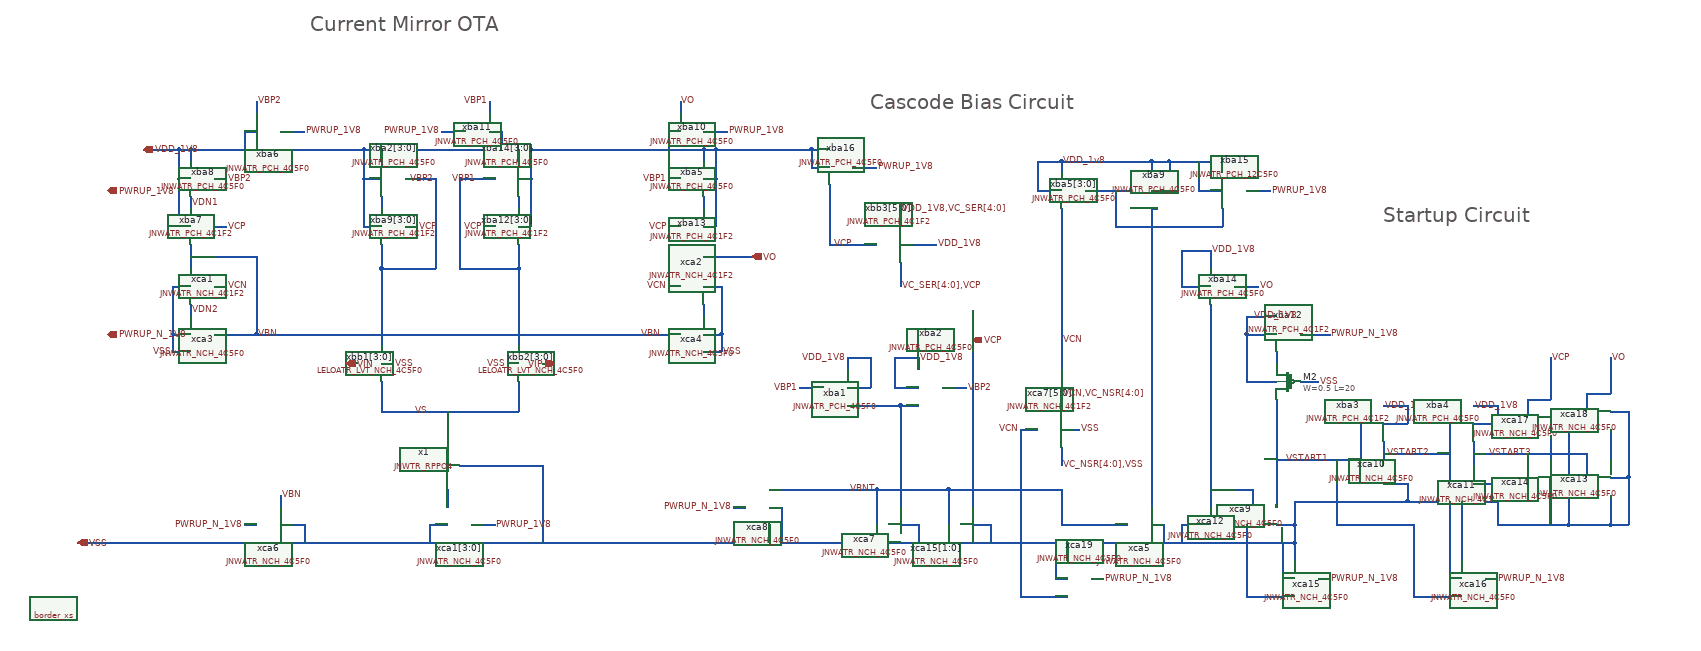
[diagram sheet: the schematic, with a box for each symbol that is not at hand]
v {xschem version=3.4.7 file_version=1.2}
G {}
K {}
V {}
S {}
E {}
T {Cascode Bias Circuit} 1430 -850 0 0 1 1 {}
T {Current Mirror OTA} 490 -980 0 0 1 1 {}
T {Startup Circuit} 2290 -660 0 0 1 1 {}
N 100 -100 210 -100 {lab=VSS}
N 210 -760 270 -760 {lab=VDD_1V8}
N 610 -370 610 -320 {lab=VS}
N 610 -320 840 -320 {lab=VS}
N 840 -370 840 -320 {lab=VS}
N 720 -320 720 -280 {lab=VS}
N 210 -100 720 -100 {lab=VSS}
N 610 -400 630 -400 {lab=VSS}
N 820 -400 840 -400 {lab=VSS}
N 580 -710 610 -710 {lab=VDD_1V8}
N 580 -760 580 -710 {lab=VDD_1V8}
N 580 -760 860 -760 {lab=VDD_1V8}
N 860 -760 860 -710 {lab=VDD_1V8}
N 840 -710 860 -710 {lab=VDD_1V8}
N 840 -760 840 -740 {lab=VDD_1V8}
N 610 -760 610 -740 {lab=VDD_1V8}
N 860 -710 860 -630 {lab=VDD_1V8}
N 840 -680 840 -660 {lab=#net1}
N 650 -710 700 -710 {lab=VBP2}
N 700 -710 700 -560 {lab=VBP2}
N 610 -560 700 -560 {lab=VBP2}
N 610 -590 610 -560 {lab=VBP2}
N 610 -560 610 -430 {lab=VBP2}
N 740 -710 800 -710 {lab=VBP1}
N 740 -710 740 -560 {lab=VBP1}
N 740 -560 840 -560 {lab=VBP1}
N 840 -600 840 -560 {lab=VBP1}
N 610 -600 610 -590 {lab=VBP2}
N 580 -710 580 -630 {lab=VDD_1V8}
N 840 -560 840 -430 {lab=VBP1}
N 1170 -760 1170 -710 {lab=VDD_1V8}
N 1150 -710 1170 -710 {lab=VDD_1V8}
N 1150 -760 1150 -740 {lab=VDD_1V8}
N 1170 -710 1170 -630 {lab=VDD_1V8}
N 1150 -680 1150 -660 {lab=#net2}
N 1150 -600 1150 -560 {lab=VO}
N 650 -630 670 -630 {lab=VCP}
N 780 -630 800 -630 {lab=VCP}
N 610 -680 610 -660 {lab=#net3}
N 1090 -710 1110 -710 {lab=VBP1}
N 1090 -630 1110 -630 {lab=VCP}
N 860 -760 1150 -760 {lab=VDD_1V8}
N 1150 -760 1170 -760 {lab=VDD_1V8}
N 270 -760 270 -710 {lab=VDD_1V8}
N 270 -710 290 -710 {lab=VDD_1V8}
N 290 -760 290 -740 {lab=VDD_1V8}
N 270 -710 270 -630 {lab=VDD_1V8}
N 290 -680 290 -660 {lab=VDN1}
N 290 -600 290 -560 {lab=VBN}
N 330 -710 350 -710 {lab=VBP2}
N 330 -630 350 -630 {lab=VCP}
N 290 -760 580 -760 {lab=VDD_1V8}
N 270 -760 290 -760 {lab=VDD_1V8}
N 290 -500 290 -480 {lab=VDN2}
N 260 -530 260 -450 {lab=VSS}
N 260 -450 290 -450 {lab=VSS}
N 260 -450 260 -420 {lab=VSS}
N 260 -420 290 -420 {lab=VSS}
N 330 -530 350 -530 {lab=VCN}
N 330 -450 400 -450 {lab=VBN}
N 400 -580 400 -450 {lab=VBN}
N 290 -580 400 -580 {lab=VBN}
N 1150 -600 1150 -560 {lab=VO}
N 1150 -500 1150 -480 {lab=#net4}
N 1180 -530 1180 -450 {lab=VSS}
N 1150 -450 1180 -450 {lab=VSS}
N 1180 -450 1180 -420 {lab=VSS}
N 1150 -420 1180 -420 {lab=VSS}
N 1090 -530 1110 -530 {lab=VCN}
N 1080 -450 1110 -450 {lab=VBN}
N 400 -450 1080 -450 {lab=VBN}
N 1150 -580 1230 -580 {lab=VO}
N 380 -790 400 -790 {lab=VDD_1V8}
N 380 -790 380 -760 {lab=VDD_1V8}
N 400 -840 400 -820 {lab=VBP2}
N 440 -790 480 -790 {lab=PWRUP_1V8}
N 790 -790 810 -790 {lab=VDD_1V8}
N 810 -790 810 -760 {lab=VDD_1V8}
N 790 -840 790 -820 {lab=VBP1}
N 710 -790 750 -790 {lab=PWRUP_1V8}
N 440 -130 480 -130 {lab=VSS}
N 480 -130 480 -100 {lab=VSS}
N 440 -180 440 -160 {lab=VBN}
N 380 -130 400 -130 {lab=PWRUP_N_1V8}
N 880 -400 900 -400 {lab=VIP}
N 550 -400 570 -400 {lab=VIN}
N 1480 -600 1510 -600 {lab=VDD_1V8}
N 1510 -600 1540 -600 {lab=VDD_1V8}
N 1400 -600 1440 -600 {lab=VCP}
N 1480 -670 1480 -630 {lab=VDD_1V8,VC_SER[4:0]}
N 1480 -570 1480 -530 {lab=VC_SER[4:0],VCP}
N 760 -100 1540 -100 {lab=VSS}
N 1280 -160 1280 -100 {lab=VSS}
N 1260 -160 1280 -160 {lab=VSS}
N 1260 -130 1260 -100 {lab=VSS}
N 1200 -160 1220 -160 {lab=PWRUP_N_1V8}
N 1750 -360 1750 -320 {lab=VCN,VC_NSR[4:0]}
N 1680 -290 1710 -290 {lab=VCN}
N 1750 -290 1780 -290 {lab=VSS}
N 1750 -260 1750 -230 {lab=VC_NSR[4:0],VSS}
N 1090 -790 1110 -790 {lab=VDD_1V8}
N 1090 -790 1090 -760 {lab=VDD_1V8}
N 1110 -840 1110 -820 {lab=VO}
N 1150 -790 1190 -790 {lab=PWRUP_1V8}
N 1540 -100 2140 -100 {lab=VSS}
N 1310 -360 1350 -360 {lab=VBP1}
N 1390 -360 1430 -360 {lab=VDD_1V8}
N 1430 -410 1430 -360 {lab=VDD_1V8}
N 1390 -410 1430 -410 {lab=VDD_1V8}
N 1390 -410 1390 -390 {lab=VDD_1V8}
N 1480 -130 1510 -130 {lab=VSS}
N 1510 -130 1510 -100 {lab=VSS}
N 1480 -100 1510 -100 {lab=VSS}
N 1480 -330 1480 -160 {lab=VBNT}
N 1440 -190 1440 -130 {lab=VBNT}
N 1440 -190 1480 -190 {lab=VBNT}
N 1710 -690 1750 -690 {lab=VDD_1v8}
N 1710 -740 1710 -690 {lab=VDD_1v8}
N 1710 -740 1750 -740 {lab=VDD_1v8}
N 1750 -740 1750 -720 {lab=VDD_1v8}
N 1750 -660 1750 -490 {lab=VCN}
N 1750 -490 1750 -390 {lab=VCN}
N 1260 -190 1440 -190 {lab=VBNT}
N 720 -100 760 -100 {lab=VSS}
N 690 -130 720 -130 {lab=VSS}
N 690 -130 690 -100 {lab=VSS}
N 760 -130 800 -130 {lab=PWRUP_1V8}
N 1600 -130 1630 -130 {lab=VSS}
N 1630 -130 1630 -100 {lab=VSS}
N 1560 -190 1560 -130 {lab=VBNT}
N 1480 -190 1560 -190 {lab=VBNT}
N 1600 -490 1600 -160 {lab=VCP}
N 2110 -130 2140 -130 {lab=VSS}
N 2140 -130 2140 -100 {lab=VSS}
N 2070 -190 2070 -130 {lab=#net5}
N 2110 -270 2110 -230 {lab=VSTART1}
N 2110 -230 2110 -160 {lab=VSTART1}
N 2290 -270 2290 -230 {lab=VSTART2}
N 2290 -200 2330 -200 {lab=VSS}
N 2330 -200 2330 -170 {lab=VSS}
N 2290 -170 2330 -170 {lab=VSS}
N 2140 -170 2290 -170 {lab=VSS}
N 2140 -170 2140 -130 {lab=VSS}
N 2250 -300 2250 -200 {lab=VSTART1}
N 2110 -240 2250 -240 {lab=VSTART1}
N 2290 -300 2330 -300 {lab=VDD_1V8}
N 2330 -330 2330 -300 {lab=VDD_1V8}
N 2290 -330 2330 -330 {lab=VDD_1V8}
N 2440 -270 2440 -230 {lab=VSTART3}
N 2440 -200 2480 -200 {lab=VSS}
N 2480 -200 2480 -170 {lab=VSS}
N 2440 -170 2480 -170 {lab=VSS}
N 2400 -300 2400 -200 {lab=VSTART2}
N 2440 -300 2480 -300 {lab=VDD_1V8}
N 2480 -330 2480 -300 {lab=VDD_1V8}
N 2440 -330 2480 -330 {lab=VDD_1V8}
N 2290 -250 2400 -250 {lab=VSTART2}
N 2480 -130 2550 -130 {lab=VSS}
N 2550 -130 2580 -130 {lab=VSS}
N 2670 -180 2670 -130 {lab=VSS}
N 2600 -130 2670 -130 {lab=VSS}
N 2670 -210 2700 -210 {lab=VSS}
N 2700 -210 2700 -130 {lab=VSS}
N 2670 -130 2700 -130 {lab=VSS}
N 2580 -130 2600 -130 {lab=VSS}
N 2510 -250 2630 -250 {lab=VSTART3}
N 2630 -250 2630 -210 {lab=VSTART3}
N 2480 -170 2480 -130 {lab=VSS}
N 2330 -170 2440 -170 {lab=VSS}
N 2110 -340 2110 -270 {lab=VSTART1}
N 2060 -370 2110 -370 {lab=VDD_1V8}
N 2060 -420 2060 -370 {lab=VDD_1V8}
N 2110 -420 2110 -400 {lab=#net6}
N 2150 -370 2180 -370 {lab=VSS}
N 2440 -250 2510 -250 {lab=VSTART3}
N 1550 -360 1590 -360 {lab=VBP2}
N 1470 -360 1510 -360 {lab=VDD_1V8}
N 1470 -410 1470 -360 {lab=VDD_1V8}
N 1470 -410 1510 -410 {lab=VDD_1V8}
N 1510 -410 1510 -390 {lab=VDD_1V8}
N 1390 -330 1480 -330 {lab=VBNT}
N 270 -630 290 -630 {lab=VDD_1V8}
N 260 -530 290 -530 {lab=VSS}
N 580 -630 610 -630 {lab=VDD_1V8}
N 840 -630 860 -630 {lab=VDD_1V8}
N 1150 -630 1170 -630 {lab=VDD_1V8}
N 1790 -690 1860 -690 {lab=#net7}
N 1750 -740 1900 -740 {lab=VDD_1v8}
N 1900 -740 1900 -720 {lab=VDD_1v8}
N 1900 -690 1930 -690 {lab=VDD_1v8}
N 1930 -740 1930 -690 {lab=VDD_1v8}
N 1900 -740 1930 -740 {lab=VDD_1v8}
N 1900 -660 1900 -160 {lab=#net7}
N 1900 -660 1910 -660 {lab=#net7}
N 1900 -130 1920 -130 {lab=VSS}
N 1920 -130 1920 -100 {lab=VSS}
N 1750 -190 1750 -130 {lab=VBNT}
N 1840 -690 1840 -630 {lab=#net7}
N 1840 -630 1900 -630 {lab=#net7}
N 1360 -600 1400 -600 {lab=VCP}
N 720 -280 720 -270 {lab=VS}
N 720 -190 720 -160 {lab=#net8}
N 740 -230 880 -230 {lab=VSS}
N 880 -230 880 -100 {lab=VSS}
N 1480 -330 1510 -330 {lab=VBNT}
N 2040 -130 2070 -130 {lab=#net5}
N 2000 -500 2000 -160 {lab=#net5}
N 1950 -590 1950 -530 {lab=VDD_1V8}
N 2000 -590 2000 -560 {lab=VDD_1V8}
N 2040 -530 2080 -530 {lab=VO}
N 2000 -190 2070 -190 {lab=#net5}
N 2570 -210 2600 -210 {lab=VSS}
N 2600 -210 2600 -130 {lab=VSS}
N 2570 -180 2570 -130 {lab=VSS}
N 2530 -250 2530 -210 {lab=VSTART3}
N 2570 -410 2570 -400 {lab=VCP}
N 1150 -530 1180 -530 {lab=VSS}
N 1950 -530 2000 -530 {lab=VDD_1V8}
N 1950 -590 2000 -590 {lab=VDD_1V8}
N 1750 -130 1860 -130 {lab=VBNT}
N 1560 -190 1750 -190 {lab=VBNT}
N 1970 -130 2000 -130 {lab=VSS}
N 1950 -130 1970 -130 {lab=VSS}
N 1950 -130 1950 -100 {lab=VSS}
N 2120 -100 2120 -40 {lab=VSS}
N 2120 -40 2140 -40 {lab=VSS}
N 2140 -100 2140 -70 {lab=VSS}
N 2180 -40 2200 -40 {lab=PWRUP_N_1V8}
N 2060 -10 2140 -10 {lab=#net5}
N 2060 -130 2060 -10 {lab=#net5}
N 2060 -450 2110 -450 {lab=VDD_1V8}
N 2060 -450 2060 -420 {lab=VDD_1V8}
N 2060 -480 2060 -450 {lab=VDD_1V8}
N 2060 -480 2110 -480 {lab=VDD_1V8}
N 2150 -450 2200 -450 {lab=PWRUP_N_1V8}
N 2400 -100 2400 -40 {lab=VSS}
N 2400 -40 2420 -40 {lab=VSS}
N 2420 -100 2420 -70 {lab=VSS}
N 2460 -40 2480 -40 {lab=PWRUP_N_1V8}
N 2340 -10 2420 -10 {lab=VSTART1}
N 2340 -130 2340 -10 {lab=VSTART1}
N 2420 -170 2420 -100 {lab=VSS}
N 2400 -170 2400 -100 {lab=VSS}
N 2210 -130 2340 -130 {lab=VSTART1}
N 2210 -240 2210 -130 {lab=VSTART1}
N 2570 -280 2570 -240 {lab=#net9}
N 2570 -310 2600 -310 {lab=VSS}
N 2600 -310 2600 -210 {lab=VSS}
N 2530 -340 2530 -310 {lab=VCP}
N 2530 -340 2570 -340 {lab=VCP}
N 2570 -400 2570 -340 {lab=VCP}
N 2670 -320 2700 -320 {lab=VSS}
N 2630 -350 2630 -320 {lab=VO}
N 2630 -350 2670 -350 {lab=VO}
N 2670 -290 2670 -240 {lab=#net10}
N 2700 -320 2700 -210 {lab=VSS}
N 2670 -410 2670 -350 {lab=VO}
N 2020 -660 2020 -630 {lab=#net7}
N 1900 -630 2020 -630 {lab=#net7}
N 2020 -740 2020 -720 {lab=VDD_1v8}
N 1930 -740 2020 -740 {lab=VDD_1v8}
N 1980 -690 2020 -690 {lab=VDD_1v8}
N 1980 -740 1980 -690 {lab=VDD_1v8}
N 2060 -690 2100 -690 {lab=PWRUP_1V8}
N 1330 -730 1360 -730 {lab=VDD_1V8}
N 1330 -760 1330 -730 {lab=VDD_1V8}
N 1330 -760 1360 -760 {lab=VDD_1V8}
N 1170 -760 1330 -760 {lab=VDD_1V8}
N 1360 -700 1360 -600 {lab=VCP}
N 1400 -730 1440 -730 {lab=PWRUP_1V8}
N 1740 -100 1740 -40 {lab=VSS}
N 1740 -40 1760 -40 {lab=VSS}
N 1760 -100 1760 -70 {lab=VSS}
N 1800 -40 1820 -40 {lab=PWRUP_N_1V8}
N 1680 -10 1760 -10 {lab=VCN}
N 1680 -290 1680 -10 {lab=VCN}
C {devices/ipin.sym} 210 -760 2 1 {name=p4 lab=VDD_1V8}
C {devices/ipin.sym} 100 -100 2 1 {name=p5 lab=VSS}
C {JNW_ATR_SKY130A/JNWATR_NCH_4C5F0.sym} 330 -450 0 1 {name=xca3}
C {devices/ipin.sym} 150 -450 2 1 {name=p9 lab=PWRUP_N_1V8}
C {devices/ipin.sym} 150 -690 2 1 {name=p10 lab=PWRUP_1V8}
C {cborder/border_xs.sym} 60 10 0 0 {user="Carsten Wulff" company="Carsten Wulff Software"}
C {LELO_ATR_SKY130A/LELOATR_LVT_NCH_4C5F0.sym} 570 -400 0 0 {name=xbb1[3:0]}
C {LELO_ATR_SKY130A/LELOATR_LVT_NCH_4C5F0.sym} 880 -400 0 1 {name=xbb2[3:0]}
C {devices/lab_wire.sym} 630 -400 0 1 {name=p1 sig_type=std_logic lab=VSS}
C {devices/lab_wire.sym} 820 -400 0 0 {name=p2 sig_type=std_logic lab=VSS}
C {devices/lab_wire.sym} 690 -320 0 0 {name=p7 sig_type=std_logic lab=VS}
C {JNW_ATR_SKY130A/JNWATR_PCH_4C5F0.sym} 650 -710 0 1 {name=xba2[3:0]}
C {JNW_ATR_SKY130A/JNWATR_PCH_4C5F0.sym} 800 -710 0 0 {name=xba14[3:0]}
C {JNW_ATR_SKY130A/JNWATR_PCH_4C5F0.sym} 1110 -710 0 0 {name=xba5}
C {devices/lab_wire.sym} 670 -630 0 1 {name=p8 sig_type=std_logic lab=VCP}
C {devices/lab_wire.sym} 780 -630 0 0 {name=p11 sig_type=std_logic lab=VCP}
C {devices/lab_wire.sym} 770 -710 0 0 {name=p12 sig_type=std_logic lab=VBP1}
C {devices/lab_wire.sym} 700 -710 0 0 {name=p14 sig_type=std_logic lab=VBP2}
C {devices/lab_wire.sym} 1090 -710 0 0 {name=p16 sig_type=std_logic lab=VBP1}
C {devices/lab_wire.sym} 1090 -630 0 0 {name=p17 sig_type=std_logic lab=VCP}
C {JNW_ATR_SKY130A/JNWATR_PCH_4C5F0.sym} 330 -710 0 1 {name=xba8}
C {devices/lab_wire.sym} 350 -710 0 1 {name=p18 sig_type=std_logic lab=VBP2
}
C {devices/lab_wire.sym} 350 -630 0 1 {name=p19 sig_type=std_logic lab=VCP}
C {devices/lab_wire.sym} 350 -530 0 1 {name=p13 sig_type=std_logic lab=VCN}
C {devices/lab_wire.sym} 400 -450 0 1 {name=p20 sig_type=std_logic lab=VBN}
C {devices/lab_wire.sym} 260 -420 0 0 {name=p21 sig_type=std_logic lab=VSS}
C {JNW_ATR_SKY130A/JNWATR_NCH_4C5F0.sym} 1110 -450 0 0 {name=xca4}
C {devices/lab_wire.sym} 1090 -530 0 0 {name=p22 sig_type=std_logic lab=VCN}
C {devices/lab_wire.sym} 1180 -420 0 1 {name=p23 sig_type=std_logic lab=VSS}
C {devices/lab_wire.sym} 1080 -450 0 0 {name=p24 sig_type=std_logic lab=VBN}
C {devices/opin.sym} 1230 -580 0 0 {name=p25 lab=VO}
C {JNW_ATR_SKY130A/JNWATR_PCH_4C5F0.sym} 440 -790 2 0 {name=xba6}
C {devices/lab_wire.sym} 480 -790 0 1 {name=p26 sig_type=std_logic lab=PWRUP_1V8
}
C {devices/lab_wire.sym} 400 -840 0 1 {name=p27 sig_type=std_logic lab=VBP2
}
C {JNW_ATR_SKY130A/JNWATR_PCH_4C5F0.sym} 750 -790 2 1 {name=xba11}
C {devices/lab_wire.sym} 710 -790 0 0 {name=p28 sig_type=std_logic lab=PWRUP_1V8
}
C {devices/lab_wire.sym} 790 -840 0 0 {name=p29 sig_type=std_logic lab=VBP1
}
C {JNW_ATR_SKY130A/JNWATR_NCH_4C5F0.sym} 400 -130 0 0 {name=xca6}
C {devices/lab_wire.sym} 380 -130 0 0 {name=p30 sig_type=std_logic lab=PWRUP_N_1V8}
C {devices/lab_wire.sym} 440 -180 0 1 {name=p31 sig_type=std_logic lab=VBN}
C {devices/ipin.sym} 900 -400 2 0 {name=p33 lab=VIP}
C {devices/ipin.sym} 550 -400 2 1 {name=p34 lab=VIN}
C {JNW_ATR_SKY130A/JNWATR_PCH_4C1F2.sym} 1440 -600 0 0 {name=xbb3[5:0]}
C {devices/lab_wire.sym} 1540 -600 0 1 {name=p40 sig_type=std_logic lab=VDD_1V8}
C {devices/lab_wire.sym} 1480 -660 0 1 {name=p41 sig_type=std_logic lab=VDD_1V8,VC_SER[4:0]}
C {devices/lab_wire.sym} 1480 -530 0 1 {name=p42 sig_type=std_logic lab=VC_SER[4:0],VCP}
C {JNW_ATR_SKY130A/JNWATR_NCH_4C1F2.sym} 1710 -290 0 0 {name=xca7[5:0]}
C {JNW_ATR_SKY130A/JNWATR_NCH_4C5F0.sym} 1220 -160 0 0 {name=xca8}
C {devices/lab_wire.sym} 1200 -160 0 0 {name=p39 sig_type=std_logic lab=PWRUP_N_1V8}
C {devices/lab_wire.sym} 1680 -290 0 0 {name=p46 sig_type=std_logic lab=VCN}
C {devices/lab_wire.sym} 1780 -290 0 1 {name=p47 sig_type=std_logic lab=VSS}
C {devices/lab_wire.sym} 1750 -350 0 1 {name=p48 sig_type=std_logic lab=VCN,VC_NSR[4:0]}
C {devices/lab_wire.sym} 1750 -230 0 1 {name=p49 sig_type=std_logic lab=VC_NSR[4:0],VSS}
C {JNW_ATR_SKY130A/JNWATR_PCH_4C5F0.sym} 1150 -790 2 0 {name=xba10}
C {devices/lab_wire.sym} 1190 -790 0 1 {name=p50 sig_type=std_logic lab=PWRUP_1V8
}
C {devices/lab_wire.sym} 1110 -840 0 1 {name=p51 sig_type=std_logic lab=VO
}
C {devices/opin.sym} 1600 -440 0 0 {name=p53 lab=VCP}
C {JNW_ATR_SKY130A/JNWATR_PCH_4C5F0.sym} 1350 -360 0 0 {name=xba1}
C {devices/lab_wire.sym} 1310 -360 0 0 {name=p57 sig_type=std_logic lab=VBP1
}
C {devices/lab_wire.sym} 1390 -410 0 0 {name=p59 sig_type=std_logic lab=VDD_1V8}
C {JNW_ATR_SKY130A/JNWATR_NCH_4C5F0.sym} 1440 -130 0 0 {name=xca7}
C {devices/lab_wire.sym} 1440 -190 0 0 {name=p60 sig_type=std_logic lab=VBNT}
C {devices/lab_wire.sym} 1400 -600 0 0 {name=p3 sig_type=std_logic lab=VCP
}
C {JNW_ATR_SKY130A/JNWATR_PCH_4C5F0.sym} 1790 -690 0 1 {name=xba5[3:0]}
C {devices/lab_wire.sym} 1750 -740 0 1 {name=p32 sig_type=std_logic lab=VDD_1v8}
C {devices/lab_wire.sym} 1750 -440 0 1 {name=p35 sig_type=std_logic lab=VCN}
C {JNW_ATR_SKY130A/JNWATR_NCH_4C5F0.sym} 760 -130 0 1 {name=xca1[3:0]}
C {devices/lab_wire.sym} 800 -130 0 1 {name=p15 sig_type=std_logic lab=PWRUP_1V8}
C {JNW_ATR_SKY130A/JNWATR_NCH_4C5F0.sym} 1560 -130 0 0 {name=xca15[1:0]}
C {JNW_ATR_SKY130A/JNWATR_NCH_4C5F0.sym} 2070 -130 0 0 {name=xca9}
C {JNW_ATR_SKY130A/JNWATR_NCH_4C5F0.sym} 2250 -200 0 0 {name=xca10}
C {JNW_ATR_SKY130A/JNWATR_PCH_4C1F2.sym} 2250 -300 0 0 {name=xba3}
C {devices/lab_wire.sym} 2290 -330 0 1 {name=p43 sig_type=std_logic lab=VDD_1V8}
C {devices/lab_wire.sym} 2200 -240 0 0 {name=p37 sig_type=std_logic lab=VSTART1}
C {JNW_ATR_SKY130A/JNWATR_NCH_4C1F2.sym} 2400 -200 0 0 {name=xca11}
C {JNW_ATR_SKY130A/JNWATR_PCH_4C5F0.sym} 2400 -300 0 0 {name=xba4}
C {devices/lab_wire.sym} 2440 -330 0 1 {name=p44 sig_type=std_logic lab=VDD_1V8}
C {JNW_ATR_SKY130A/JNWATR_NCH_4C5F0.sym} 2630 -210 0 0 {name=xca13}
C {devices/lab_wire.sym} 2670 -410 0 1 {name=p52 sig_type=std_logic lab=VO}
C {devices/lab_wire.sym} 2370 -250 0 0 {name=p54 sig_type=std_logic lab=VSTART2}
C {devices/lab_wire.sym} 2540 -250 0 0 {name=p58 sig_type=std_logic lab=VSTART3}
C {devices/lab_wire.sym} 2180 -370 0 1 {name=p36 sig_type=std_logic lab=VSS}
C {sky130_fd_pr/pfet_01v8.sym} 2130 -370 0 1 {name=M2
W=0.5
L=20
nf=1
mult=1
ad="'int((nf+1)/2) * W/nf * 0.29'" 
pd="'2*int((nf+1)/2) * (W/nf + 0.29)'"
as="'int((nf+2)/2) * W/nf * 0.29'" 
ps="'2*int((nf+2)/2) * (W/nf + 0.29)'"
nrd="'0.29 / W'" nrs="'0.29 / W'"
sa=0 sb=0 sd=0
model=pfet_01v8
spiceprefix=X
}
C {JNW_ATR_SKY130A/JNWATR_PCH_4C5F0.sym} 1550 -360 0 1 {name=xba2}
C {devices/lab_wire.sym} 1590 -360 0 1 {name=p45 sig_type=std_logic lab=VBP2}
C {devices/lab_wire.sym} 1510 -410 0 1 {name=p55 sig_type=std_logic lab=VDD_1V8}
C {JNW_ATR_SKY130A/JNWATR_PCH_4C1F2.sym} 330 -630 0 1 {name=xba7}
C {JNW_ATR_SKY130A/JNWATR_NCH_4C1F2.sym} 330 -530 0 1 {name=xca1}
C {JNW_ATR_SKY130A/JNWATR_NCH_4C1F2.sym} 1110 -530 0 0 {name=xca2}
C {JNW_ATR_SKY130A/JNWATR_PCH_4C1F2.sym} 650 -630 0 1 {name=xba9[3:0]}
C {JNW_ATR_SKY130A/JNWATR_PCH_4C1F2.sym} 800 -630 0 0 {name=xba12[3:0]}
C {JNW_ATR_SKY130A/JNWATR_PCH_4C1F2.sym} 1110 -630 0 0 {name=xba13}
C {JNW_ATR_SKY130A/JNWATR_PCH_4C5F0.sym} 1860 -690 0 0 {name=xba9}
C {JNW_ATR_SKY130A/JNWATR_NCH_4C5F0.sym} 1860 -130 0 0 {name=xca5}
C {JNW_TR_SKY130A/JNWTR_RPPO4.sym} 720 -190 3 0 {name=x1 }
C {JNW_ATR_SKY130A/JNWATR_PCH_4C5F0.sym} 2040 -530 0 1 {name=xba14}
C {JNW_ATR_SKY130A/JNWATR_NCH_4C5F0.sym} 2040 -130 0 1 {name=xca12}
C {devices/lab_wire.sym} 2080 -530 0 1 {name=p6 sig_type=std_logic lab=VO}
C {JNW_ATR_SKY130A/JNWATR_NCH_4C5F0.sym} 2530 -210 0 0 {name=xca14}
C {devices/lab_wire.sym} 2570 -410 0 1 {name=p56 sig_type=std_logic lab=VCP}
C {devices/lab_wire.sym} 2000 -590 0 1 {name=p61 sig_type=std_logic lab=VDD_1V8}
C {devices/lab_wire.sym} 290 -670 0 1 {name=p62 sig_type=std_logic lab=VDN1
}
C {devices/lab_wire.sym} 290 -490 0 1 {name=p63 sig_type=std_logic lab=VDN2
}
C {JNW_ATR_SKY130A/JNWATR_NCH_4C5F0.sym} 2180 -40 2 0 {name=xca15}
C {devices/lab_wire.sym} 2200 -40 2 0 {name=p64 sig_type=std_logic lab=PWRUP_N_1V8}
C {JNW_ATR_SKY130A/JNWATR_PCH_4C1F2.sym} 2150 -450 0 1 {name=xba12}
C {devices/lab_wire.sym} 2070 -480 0 1 {name=p38 sig_type=std_logic lab=VDD_1V8}
C {devices/lab_wire.sym} 2200 -450 0 1 {name=p65 sig_type=std_logic lab=PWRUP_N_1V8}
C {JNW_ATR_SKY130A/JNWATR_NCH_4C5F0.sym} 2460 -40 2 0 {name=xca16}
C {devices/lab_wire.sym} 2480 -40 2 0 {name=p66 sig_type=std_logic lab=PWRUP_N_1V8}
C {JNW_ATR_SKY130A/JNWATR_NCH_4C5F0.sym} 2530 -310 0 0 {name=xca17}
C {JNW_ATR_SKY130A/JNWATR_NCH_4C5F0.sym} 2630 -320 0 0 {name=xca18}
C {JNW_ATR_SKY130A/JNWATR_PCH_12C5F0.sym} 2060 -690 0 1 {name=xba15}
C {devices/lab_wire.sym} 2100 -690 0 1 {name=p67 sig_type=std_logic lab=PWRUP_1V8
}
C {JNW_ATR_SKY130A/JNWATR_PCH_4C5F0.sym} 1400 -730 0 1 {name=xba16}
C {devices/lab_wire.sym} 1440 -730 0 1 {name=p68 sig_type=std_logic lab=PWRUP_1V8
}
C {JNW_ATR_SKY130A/JNWATR_NCH_4C5F0.sym} 1800 -40 2 0 {name=xca19}
C {devices/lab_wire.sym} 1820 -40 2 0 {name=p69 sig_type=std_logic lab=PWRUP_N_1V8}
